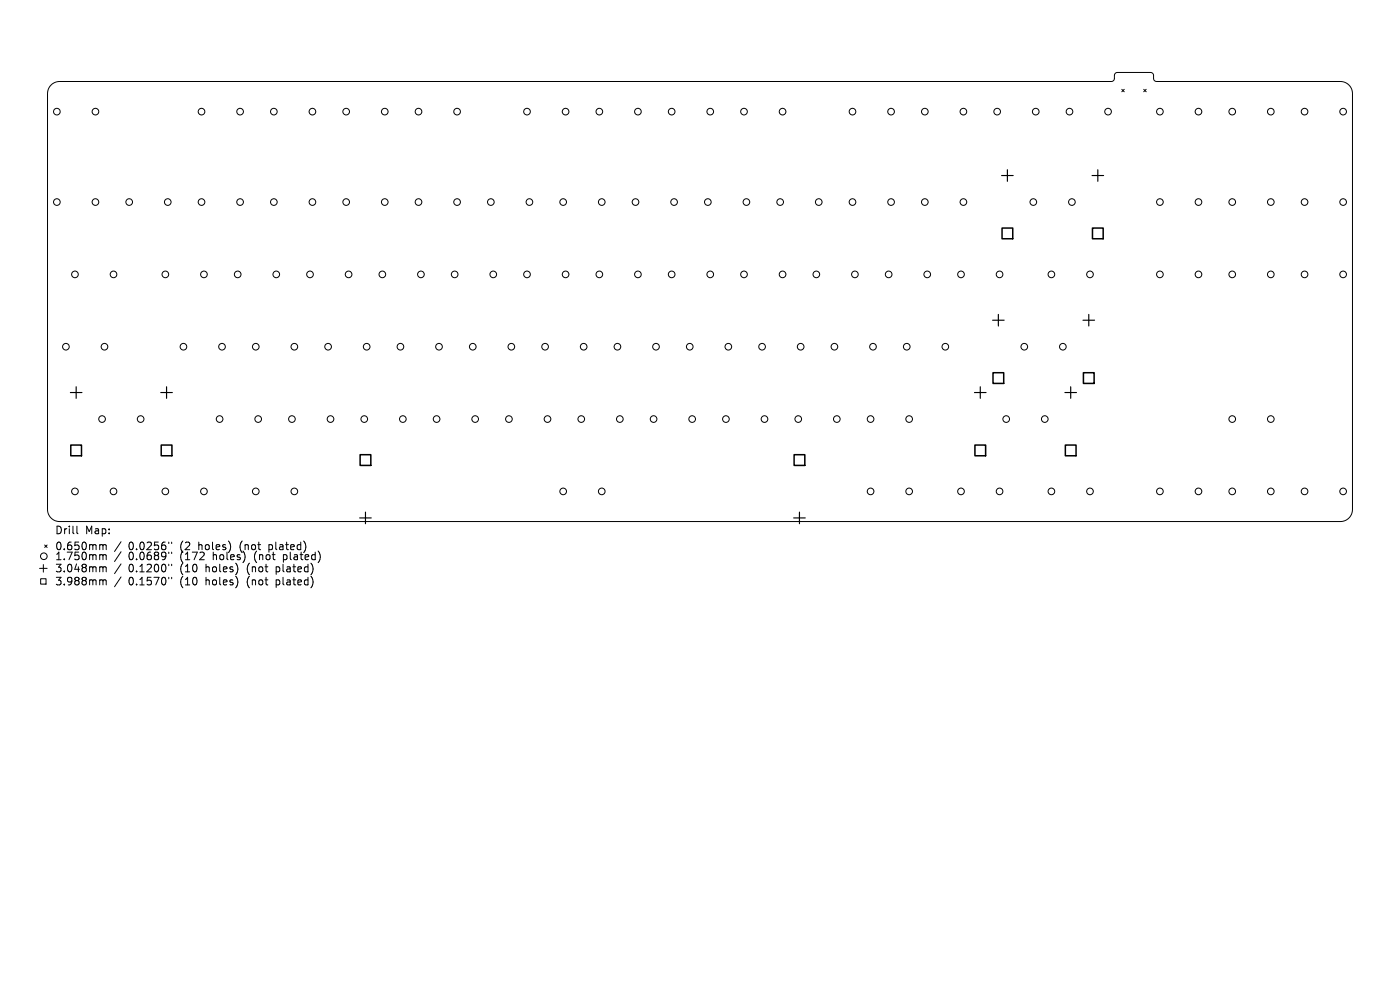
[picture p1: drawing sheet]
<svg xmlns="http://www.w3.org/2000/svg" width="297mm" height="210mm" viewBox="0 0 297 210" stroke-linecap="round" stroke-linejoin="round" font-family="sans-serif">
<defs><g id="words">
<g font-size="2.2">
<text x="11.6" y="113.5">Drill</text>
<text x="18.1" y="113.5">Map:</text>
<text x="11.6" y="116.9">0.650mm</text>
<text x="11.6" y="119">1.750mm</text>
<text x="27.3" y="116.9">0.0256&quot;</text>
<text x="27.3" y="119">0.0689&quot;</text>
<text x="38.3" y="116.9">(2</text>
<text x="38.3" y="119">(172</text>
<text x="42.3" y="116.9">holes)</text>
<text x="45.4" y="119">holes)</text>
<text x="51.2" y="116.9">(not</text>
<text x="54.3" y="119">(not</text>
<text x="57.5" y="116.9">plated)</text>
<text x="60.6" y="119">plated)</text>
<text x="11.6" y="121.6">3.048mm</text>
<text x="11.6" y="124.4">3.988mm</text>
<text x="27.3" y="121.6">0.1200&quot;</text>
<text x="27.3" y="124.4">0.1570&quot;</text>
<text x="38.3" y="121.6">(10</text>
<text x="38.3" y="124.4">(10</text>
<text x="43.9" y="121.6">holes)</text>
<text x="43.9" y="124.4">holes)</text>
<text x="52.8" y="121.6">(not</text>
<text x="52.8" y="124.4">(not</text>
<text x="59.1" y="121.6">plated)</text>
<text x="59.1" y="124.4">plated)</text>
</g>
</g></defs>
<g fill="none" stroke="#000" stroke-width=".21">
<path d="M10.8 18l.7-.5 1.1-.2h223.2l.5-.4 .3-1.3 .5-.2h7.1l.5 .3 .1 1.2 .6 .4h39a2.56 2.56 0 0 1 2.5 2.5v88.3a2.56 2.56 0 0 1-2.5 2.5h-271.8a2.56 2.56 0 0 1-2.5-2.5v-88.3l.1-.8zM238 18.9l.5 .6M238.5 18.9l-.5 .6M242.6 18.9l.6 .6M243.2 18.9l-.6 .6M9.2 119.8v1.6M9.5 115.6l.5 .5M10 115.6l-.5 .5M16.3 111.6v1.4l.2 .2M21.4 115.5l.4 .3M21.4 117.7l.4 .2M21.8 115.8l.3-.3 .4 .1v1"/>
<path d="M21.8 115.8v.8M21.8 117.9v.8M21.8 117.9l.3-.2h.4v1M25.7 114.9l-1.4 2.1M25.7 117l-1.4 2.1M25.7 119.6l-1.4 2.1M35.8 115v.3M35.8 117.1v.3M35.8 119.7v.3M36.4 115v.3M36.4 117.1v.3M36.4 119.7v.3"/>
<path d="M8.4 120.6h1.6M8.6 122.8h1.2v1.1h-1.2zM21.4 120.2l.4 .3M21.4 123l.4 .2M21.8 120.5v.8M21.8 123.2v.9M21.8 120.5l.3-.3 .4 .1v1M21.8 123.2l.3-.2 .4 .1v1M25.7 122.4l-1.4 2.1M35.8 122.5v.3M36.4 122.5v.3"/>
<circle cx="12.1" cy="23.7" r=".7"/>
<circle cx="20.2" cy="23.7" r=".7"/>
<circle cx="42.8" cy="23.7" r=".7"/>
<circle cx="50.9" cy="23.7" r=".7"/>
<circle cx="58.1" cy="23.7" r=".7"/>
<circle cx="66.3" cy="23.7" r=".7"/>
<circle cx="73.4" cy="23.7" r=".7"/>
<circle cx="81.6" cy="23.7" r=".7"/>
<circle cx="88.8" cy="23.7" r=".7"/>
<circle cx="97" cy="23.7" r=".7"/>
<circle cx="111.8" cy="23.7" r=".7"/>
<circle cx="120" cy="23.7" r=".7"/>
<circle cx="127.1" cy="23.7" r=".7"/>
<circle cx="135.3" cy="23.7" r=".7"/>
<circle cx="142.5" cy="23.7" r=".7"/>
<circle cx="150.7" cy="23.7" r=".7"/>
<circle cx="157.8" cy="23.7" r=".7"/>
<circle cx="166" cy="23.7" r=".7"/>
<circle cx="180.9" cy="23.7" r=".7"/>
<circle cx="189" cy="23.7" r=".7"/>
<circle cx="196.2" cy="23.7" r=".7"/>
<circle cx="204.4" cy="23.7" r=".7"/>
<circle cx="211.5" cy="23.7" r=".7"/>
<circle cx="219.7" cy="23.7" r=".7"/>
<circle cx="226.9" cy="23.7" r=".7"/>
<circle cx="235.1" cy="23.7" r=".7"/>
<circle cx="246.1" cy="23.7" r=".7"/>
<circle cx="254.3" cy="23.7" r=".7"/>
<circle cx="261.4" cy="23.7" r=".71"/>
<circle cx="269.6" cy="23.7" r=".71"/>
<circle cx="276.8" cy="23.7" r=".7"/>
<circle cx="284.9" cy="23.7" r=".71"/>
<circle cx="12.1" cy="42.9" r=".7"/>
<circle cx="15.9" cy="58.2" r=".7"/>
<circle cx="20.2" cy="42.9" r=".7"/>
<circle cx="24.1" cy="58.2" r=".7"/>
<circle cx="27.4" cy="42.9" r=".7"/>
<circle cx="35.1" cy="58.2" r=".7"/>
<circle cx="35.6" cy="42.9" r=".7"/>
<circle cx="42.8" cy="42.9" r=".7"/>
<circle cx="43.3" cy="58.2" r=".7"/>
<circle cx="50.4" cy="58.2" r=".7"/>
<circle cx="50.9" cy="42.9" r=".7"/>
<circle cx="58.1" cy="42.9" r=".7"/>
<circle cx="58.6" cy="58.2" r=".7"/>
<circle cx="65.8" cy="58.2" r=".7"/>
<circle cx="66.3" cy="42.9" r=".7"/>
<circle cx="73.4" cy="42.9" r=".7"/>
<circle cx="74" cy="58.2" r=".7"/>
<circle cx="81.1" cy="58.2" r=".7"/>
<circle cx="81.6" cy="42.9" r=".7"/>
<circle cx="88.8" cy="42.9" r=".7"/>
<circle cx="89.3" cy="58.2" r=".7"/>
<circle cx="96.5" cy="58.2" r=".7"/>
<circle cx="97" cy="42.9" r=".7"/>
<circle cx="104.1" cy="42.9" r=".7"/>
<circle cx="104.6" cy="58.2" r=".7"/>
<circle cx="111.8" cy="58.2" r=".7"/>
<circle cx="112.3" cy="42.9" r=".7"/>
<circle cx="119.5" cy="42.9" r=".7"/>
<circle cx="120" cy="58.2" r=".7"/>
<circle cx="127.1" cy="58.2" r=".7"/>
<circle cx="127.7" cy="42.9" r=".7"/>
<circle cx="134.8" cy="42.9" r=".7"/>
<circle cx="135.3" cy="58.2" r=".7"/>
<circle cx="142.5" cy="58.2" r=".7"/>
<circle cx="143" cy="42.9" r=".7"/>
<circle cx="150.2" cy="42.9" r=".7"/>
<circle cx="150.7" cy="58.2" r=".7"/>
<circle cx="157.8" cy="58.2" r=".7"/>
<circle cx="158.3" cy="42.9" r=".7"/>
<circle cx="165.5" cy="42.9" r=".7"/>
<circle cx="166" cy="58.2" r=".7"/>
<circle cx="173.2" cy="58.2" r=".7"/>
<circle cx="173.7" cy="42.9" r=".7"/>
<circle cx="180.9" cy="42.9" r=".7"/>
<circle cx="181.4" cy="58.2" r=".7"/>
<circle cx="188.5" cy="58.2" r=".7"/>
<circle cx="189" cy="42.9" r=".7"/>
<circle cx="196.2" cy="42.9" r=".7"/>
<circle cx="196.7" cy="58.2" r=".7"/>
<circle cx="203.9" cy="58.2" r=".7"/>
<circle cx="204.4" cy="42.9" r=".7"/>
<circle cx="212.1" cy="58.2" r=".7"/>
<circle cx="219.2" cy="42.9" r=".7"/>
<circle cx="223" cy="58.2" r=".7"/>
<circle cx="227.4" cy="42.9" r=".7"/>
<circle cx="231.2" cy="58.2" r=".7"/>
<circle cx="246.1" cy="58.2" r=".7"/>
<circle cx="246.1" cy="42.9" r=".7"/>
<circle cx="254.3" cy="58.2" r=".7"/>
<circle cx="254.3" cy="42.9" r=".7"/>
<circle cx="261.4" cy="58.2" r=".7"/>
<circle cx="261.4" cy="42.9" r=".71"/>
<circle cx="269.6" cy="58.2" r=".7"/>
<circle cx="269.6" cy="42.9" r=".71"/>
<circle cx="276.8" cy="58.2" r=".7"/>
<circle cx="276.8" cy="42.9" r=".7"/>
<circle cx="284.9" cy="58.2" r=".7"/>
<circle cx="284.9" cy="42.9" r=".71"/>
<circle cx="14" cy="73.6" r=".7"/>
<circle cx="22.2" cy="73.6" r=".7"/>
<circle cx="38.9" cy="73.6" r=".7"/>
<circle cx="47.1" cy="73.6" r=".7"/>
<circle cx="54.3" cy="73.6" r=".7"/>
<circle cx="62.4" cy="73.6" r=".7"/>
<circle cx="69.6" cy="73.6" r=".7"/>
<circle cx="77.8" cy="73.6" r=".7"/>
<circle cx="84.9" cy="73.6" r=".7"/>
<circle cx="93.1" cy="73.6" r=".7"/>
<circle cx="100.3" cy="73.6" r=".7"/>
<circle cx="108.5" cy="73.6" r=".7"/>
<circle cx="115.6" cy="73.6" r=".7"/>
<circle cx="123.8" cy="73.6" r=".7"/>
<circle cx="131" cy="73.6" r=".7"/>
<circle cx="139.2" cy="73.6" r=".7"/>
<circle cx="146.3" cy="73.6" r=".7"/>
<circle cx="154.5" cy="73.6" r=".7"/>
<circle cx="161.7" cy="73.6" r=".7"/>
<circle cx="169.9" cy="73.6" r=".7"/>
<circle cx="177" cy="73.6" r=".7"/>
<circle cx="185.2" cy="73.6" r=".7"/>
<circle cx="192.4" cy="73.6" r=".7"/>
<circle cx="200.5" cy="73.6" r=".7"/>
<circle cx="217.3" cy="73.6" r=".7"/>
<circle cx="225.5" cy="73.6" r=".7"/>
<circle cx="21.7" cy="88.9" r=".7"/>
<circle cx="29.8" cy="88.9" r=".7"/>
<circle cx="46.6" cy="88.9" r=".7"/>
<circle cx="54.8" cy="88.9" r=".7"/>
<circle cx="61.9" cy="88.9" r=".7"/>
<circle cx="70.1" cy="88.9" r=".7"/>
<circle cx="77.3" cy="88.9" r=".7"/>
<circle cx="85.5" cy="88.9" r=".7"/>
<circle cx="92.6" cy="88.9" r=".7"/>
<circle cx="100.8" cy="88.9" r=".7"/>
<circle cx="108" cy="88.9" r=".7"/>
<circle cx="116.1" cy="88.9" r=".7"/>
<circle cx="123.3" cy="88.9" r=".7"/>
<circle cx="131.5" cy="88.9" r=".7"/>
<circle cx="138.7" cy="88.9" r=".7"/>
<circle cx="146.8" cy="88.9" r=".7"/>
<circle cx="154" cy="88.9" r=".7"/>
<circle cx="162.2" cy="88.9" r=".7"/>
<circle cx="169.3" cy="88.9" r=".7"/>
<circle cx="177.5" cy="88.9" r=".7"/>
<circle cx="184.7" cy="88.9" r=".7"/>
<circle cx="192.9" cy="88.9" r=".7"/>
<circle cx="213.5" cy="88.9" r=".7"/>
<circle cx="221.6" cy="88.9" r=".7"/>
<circle cx="261.4" cy="88.9" r=".71"/>
<circle cx="269.6" cy="88.9" r=".71"/>
<circle cx="9.3" cy="118" r=".7"/>
<circle cx="15.9" cy="104.2" r=".7"/>
<circle cx="24.1" cy="104.2" r=".7"/>
<circle cx="35.1" cy="104.2" r=".7"/>
<circle cx="43.3" cy="104.2" r=".7"/>
<circle cx="54.3" cy="104.2" r=".7"/>
<circle cx="62.4" cy="104.2" r=".7"/>
<circle cx="119.5" cy="104.2" r=".7"/>
<circle cx="127.7" cy="104.2" r=".7"/>
<circle cx="184.7" cy="104.2" r=".7"/>
<circle cx="192.9" cy="104.2" r=".7"/>
<circle cx="203.9" cy="104.2" r=".7"/>
<circle cx="212.1" cy="104.2" r=".7"/>
<circle cx="223" cy="104.2" r=".7"/>
<circle cx="231.2" cy="104.2" r=".7"/>
<circle cx="246.1" cy="104.2" r=".7"/>
<circle cx="254.3" cy="104.2" r=".7"/>
<circle cx="261.4" cy="104.2" r=".71"/>
<circle cx="269.6" cy="104.2" r=".71"/>
<circle cx="276.8" cy="104.2" r=".7"/>
<circle cx="284.9" cy="104.2" r=".71"/>
</g>
<g fill="none" stroke="#000" stroke-width=".25">
<path d="M212.5 37.2h2.4M213.7 36v2.5M231.7 37.2h2.4M232.9 36v2.5M210.6 67.9h2.4M211.8 66.7v2.5M229.8 67.9h2.4M231 66.7v2.5M14.9 83.3h2.5M16.2 82v2.5M34.1 83.3h2.5M35.3 82v2.5"/>
<path d="M206.7 83.3h2.5M208 82v2.5M225.9 83.3h2.5M227.1 82v2.5M76.3 109.9h2.5M77.5 108.6v2.5M168.4 109.9h2.4M169.6 108.6v2.5"/>
</g>
<path d="M212.6 48.4h2.3v2.2h-2.3zM231.8 48.4h2.2v2.2h-2.2zM210.7 79.1h2.2v2.2h-2.2zM229.8 79.1h2.3v2.2h-2.3zM15 94.4h2.3v2.3h-2.3zM34.2 94.4h2.3v2.3h-2.3zM76.4 96.5h2.3v2.2h-2.3zM168.5 96.5h2.2v2.2h-2.2zM206.8 94.4h2.3v2.3h-2.3zM226 94.4h2.3v2.3h-2.3z" fill="none" stroke="#000" stroke-width=".32"/>
<use href="#words"/>
</svg>
